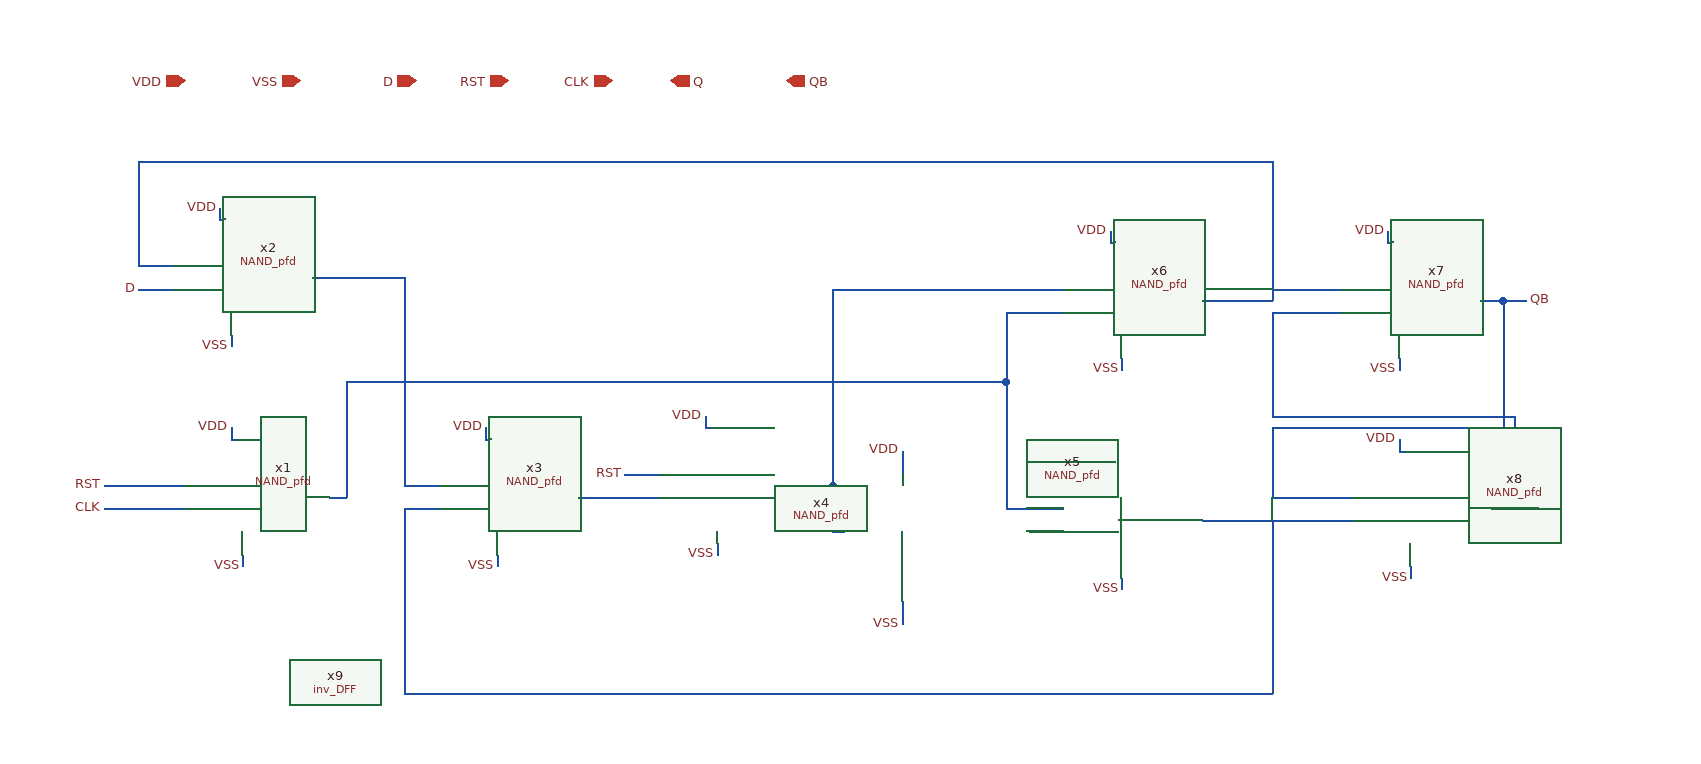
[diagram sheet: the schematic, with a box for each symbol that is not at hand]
v {xschem version=3.1.0 file_version=1.2
}
G {}
K {}
V {}
S {}
E {}
N 160 -120 160 -110 {
lab=VDD}
N 90 -70 110 -70 {
lab=#net1}
N 90 -50 110 -50 {
lab=D}
N 240 -60 260 -60 {
lab=#net2}
N 170 -10 170 0 {
lab=VSS}
N 170 70 170 80 {
lab=VDD}
N 100 120 120 120 {
lab=RST}
N 100 140 120 140 {
lab=CLK}
N 180 180 180 190 {
lab=VSS}
N 390 70 390 80 {
lab=VDD}
N 320 120 340 120 {
lab=#net2}
N 320 140 340 140 {
lab=#net3}
N 470 130 490 130 {
lab=#net4}
N 400 180 400 190 {
lab=VSS}
N 580 60 580 70 {
lab=VDD}
N 510 110 530 110 {
lab=RST}
N 510 130 530 130 {
lab=#net4}
N 660 120 680 120 {
lab=#net5}
N 590 170 590 180 {
lab=VSS}
N 930 -100 930 -90 {
lab=VDD}
N 860 -50 880 -50 {
lab=#net5}
N 860 -30 880 -30 {
lab=#net6}
N 1010 -40 1030 -40 {
lab=#net1}
N 940 10 940 20 {
lab=VSS}
N 930 90 930 100 {
lab=VDD}
N 860 160 880 160 {
lab=#net7}
N 1010 150 1030 150 {
lab=#net3}
N 940 200 940 210 {
lab=VSS}
N 1170 -100 1170 -90 {
lab=VDD}
N 1100 -50 1120 -50 {
lab=#net1}
N 1100 -30 1120 -30 {
lab=Q}
N 1250 -40 1270 -40 {
lab=QB}
N 1180 10 1180 20 {
lab=VSS}
N 1180 80 1180 90 {
lab=VDD}
N 1110 130 1130 130 {
lab=QB}
N 1110 150 1130 150 {
lab=#net3}
N 1260 140 1280 140 {
lab=Q}
N 1190 190 1190 200 {
lab=VSS}
N 750 90 750 110 {
lab=VDD}
N 750 220 750 240 {
lab=VSS}
N 690 160 700 160 {
lab=#net5}
N 690 140 690 160 {
lab=#net5}
N 60 140 100 140 {
lab=CLK}
N 60 120 100 120 {
lab=RST}
N 490 130 510 130 {
lab=#net4}
N 260 -60 300 -60 {
lab=#net2}
N 320 -60 320 120 {
lab=#net2}
N 270 30 270 130 {
lab=#net6}
N 270 30 840 30 {
lab=#net6}
N 840 -30 840 30 {
lab=#net6}
N 840 -30 860 -30 {
lab=#net6}
N 690 120 690 140 {
lab=#net5}
N 680 120 690 120 {
lab=#net5}
N 840 140 880 140 {
lab=#net6}
N 840 30 840 140 {
lab=#net6}
N 690 -50 860 -50 {
lab=#net5}
N 90 -160 90 -70 {
lab=#net1}
N 90 -160 1070 -160 {
lab=#net1}
N 1070 -160 1070 -40 {
lab=#net1}
N 1070 -50 1100 -50 {
lab=#net1}
N 1030 -40 1070 -40 {
lab=#net1}
N 1070 -30 1100 -30 {
lab=Q}
N 1070 60 1280 60 {
lab=Q}
N 1070 130 1110 130 {
lab=QB}
N 1070 70 1270 70 {
lab=QB}
N 1270 -40 1290 -40 {
lab=QB}
N 1280 140 1300 140 {
lab=Q}
N 1030 150 1110 150 {
lab=#net3}
N 1070 160 1070 300 {
lab=#net3}
N 320 300 1070 300 {
lab=#net3}
N 320 140 320 300 {
lab=#net3}
N 1070 150 1070 160 {
lab=#net3}
N 1070 -30 1070 -20 {
lab=Q}
N 690 -50 690 120 {
lab=#net5}
N 300 -60 320 -60 {
lab=#net2}
N 1280 70 1280 140 {
lab=Q}
N 1070 70 1070 130 {
lab=QB}
N 1270 -40 1270 70 {
lab=QB}
N 1280 60 1280 70 {
lab=Q}
N 1070 -20 1070 60 {
lab=Q}
N 120 120 130 120 {
lab=RST}
N 120 140 130 140 {
lab=CLK}
N 170 80 175 80 {
lab=VDD}
N 255 130 270 130 {
lab=#net6}
N 110 -50 120 -50 {
lab=D}
N 110 -70 120 -70 {
lab=#net1}
N 160 -110 165 -110 {
lab=VDD}
N 340 120 350 120 {
lab=#net2}
N 340 140 350 140 {
lab=#net3}
N 390 80 395 80 {
lab=VDD}
N 530 110 540 110 {
lab=RST}
N 530 130 540 130 {
lab=#net4}
N 580 70 585 70 {
lab=VDD}
N 880 -50 890 -50 {
lab=#net5}
N 880 -30 890 -30 {
lab=#net6}
N 930 -90 935 -90 {
lab=VDD}
N 930 100 935 100 {
lab=VDD}
N 880 140 890 140 {
lab=#net6}
N 880 160 890 160 {
lab=#net7}
N 1120 -50 1130 -50 {
lab=#net1}
N 1120 -30 1130 -30 {
lab=Q}
N 1170 -90 1175 -90 {
lab=VDD}
N 1130 130 1140 130 {
lab=QB}
N 1130 150 1140 150 {
lab=#net3}
N 1180 90 1185 90 {
lab=VDD}
C {devices/lab_pin.sym} 160 -120 0 0 {name=p1 sig_type=std_logic lab=VDD}
C {devices/lab_pin.sym} 170 0 3 0 {name=p2 sig_type=std_logic lab=VSS}
C {devices/lab_pin.sym} 170 70 0 0 {name=p3 sig_type=std_logic lab=VDD}
C {devices/lab_pin.sym} 180 190 3 0 {name=p4 sig_type=std_logic lab=VSS}
C {devices/lab_pin.sym} 390 70 0 0 {name=p5 sig_type=std_logic lab=VDD}
C {devices/lab_pin.sym} 400 190 3 0 {name=p6 sig_type=std_logic lab=VSS}
C {devices/lab_pin.sym} 580 60 0 0 {name=p7 sig_type=std_logic lab=VDD}
C {devices/lab_pin.sym} 590 180 3 0 {name=p8 sig_type=std_logic lab=VSS}
C {devices/lab_pin.sym} 930 -100 0 0 {name=p9 sig_type=std_logic lab=VDD}
C {devices/lab_pin.sym} 940 20 3 0 {name=p10 sig_type=std_logic lab=VSS}
C {devices/lab_pin.sym} 930 90 0 0 {name=p11 sig_type=std_logic lab=VDD}
C {devices/lab_pin.sym} 940 210 3 0 {name=p12 sig_type=std_logic lab=VSS}
C {devices/lab_pin.sym} 1170 -100 0 0 {name=p13 sig_type=std_logic lab=VDD}
C {devices/lab_pin.sym} 1180 20 3 0 {name=p14 sig_type=std_logic lab=VSS}
C {devices/lab_pin.sym} 1180 80 0 0 {name=p15 sig_type=std_logic lab=VDD}
C {devices/lab_pin.sym} 1190 200 3 0 {name=p16 sig_type=std_logic lab=VSS}
C {devices/lab_pin.sym} 750 90 0 0 {name=p17 sig_type=std_logic lab=VDD}
C {devices/lab_pin.sym} 750 240 3 0 {name=p18 sig_type=std_logic lab=VSS}
C {devices/lab_pin.sym} 60 140 0 0 {name=p19 sig_type=std_logic lab=CLK
}
C {devices/lab_pin.sym} 60 120 0 0 {name=p20 sig_type=std_logic lab=RST
}
C {devices/lab_pin.sym} 90 -50 0 0 {name=p21 sig_type=std_logic lab=D

}
C {devices/lab_pin.sym} 510 110 0 0 {name=p22 sig_type=std_logic lab=RST
}
C {devices/lab_pin.sym} 1290 -40 2 0 {name=p23 sig_type=std_logic lab=QB
}
C {devices/lab_pin.sym} 1290 140 2 0 {name=p24 sig_type=std_logic lab=Q
}
C {devices/iopin.sym} 130 -230 0 0 {name=p25 lab=VDD}
C {devices/iopin.sym} 230 -230 0 0 {name=p26 lab=VSS
}
C {devices/ipin.sym} 330 -230 0 0 {name=p27 lab=D}
C {devices/ipin.sym} 410 -230 0 0 {name=p28 lab=RST}
C {devices/ipin.sym} 500 -230 0 0 {name=p29 lab=CLK}
C {devices/opin.sym} 550 -230 0 0 {name=p30 lab=Q}
C {devices/opin.sym} 650 -230 0 0 {name=p32 lab=QB}
C {NAND_pfd.sym} 210 160 0 0 {name=x1}
C {NAND_pfd.sym} 200 -30 0 0 {name=x2}
C {NAND_pfd.sym} 430 160 0 0 {name=x3}
C {NAND_pfd.sym} 620 150 0 0 {name=x4}
C {NAND_pfd.sym} 970 180 0 0 {name=x5}
C {NAND_pfd.sym} 970 -10 0 0 {name=x6}
C {NAND_pfd.sym} 1210 -10 0 0 {name=x7}
C {NAND_pfd.sym} 1220 170 0 0 {name=x8}
C {inv_DFF.sym} 260 290 0 0 {name=x9}
